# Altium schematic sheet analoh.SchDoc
size A4

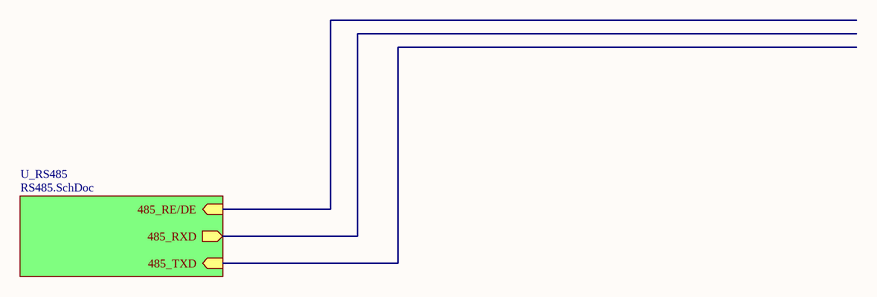
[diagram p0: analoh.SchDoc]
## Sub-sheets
U_RS485 = RS485.SchDoc: 485_RE/DE (in), 485_RXD (out), 485_TXD (in)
